VERSION 5.7 ;
BUSBITCHARS "[]" ;
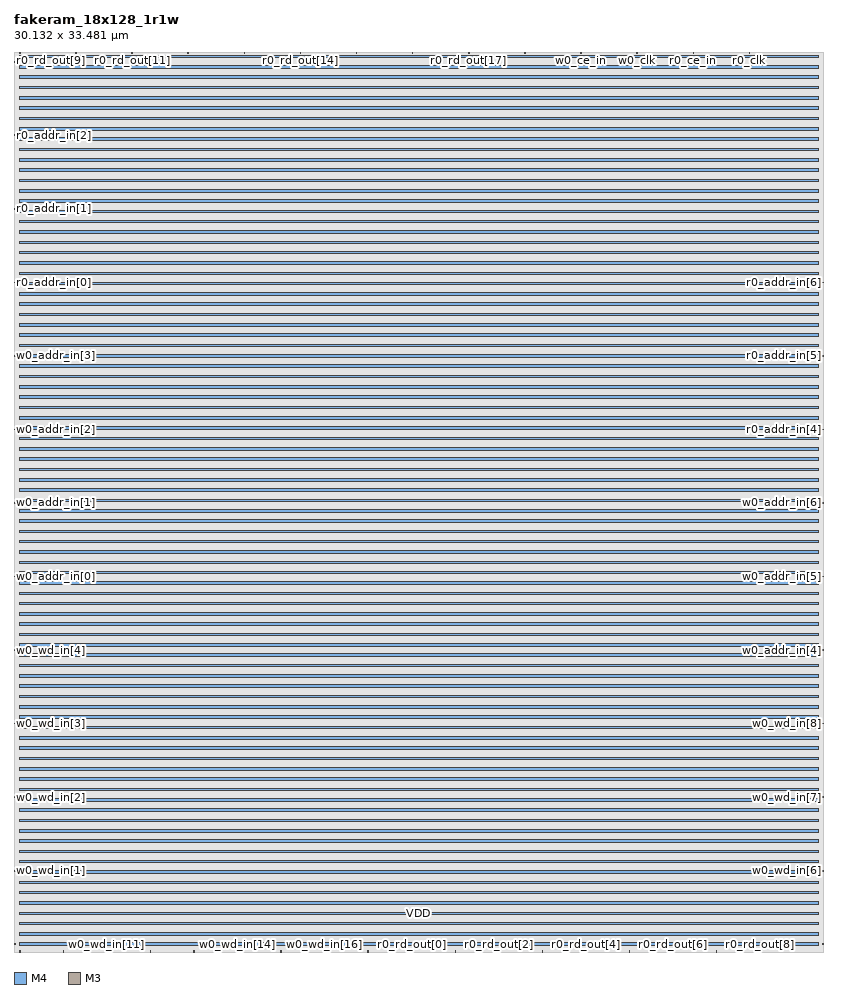
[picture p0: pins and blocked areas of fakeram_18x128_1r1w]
MACRO fakeram_18x128_1r1w
  FOREIGN fakeram_18x128_1r1w 0 0 ;
  SYMMETRY X Y R90 ;
  SIZE 30.132 BY 33.481 ;
  CLASS BLOCK ;
  PIN w0_wd_in[0]
    DIRECTION INPUT ;
    USE SIGNAL ;
    SHAPE ABUTMENT ;
    PORT
      LAYER M4 ;
      RECT 0.000 0.276 0.072 0.300 ;
    END
  END w0_wd_in[0]
  PIN w0_wd_in[1]
    DIRECTION INPUT ;
    USE SIGNAL ;
    SHAPE ABUTMENT ;
    PORT
      LAYER M4 ;
      RECT 0.000 3.012 0.072 3.036 ;
    END
  END w0_wd_in[1]
  PIN w0_wd_in[2]
    DIRECTION INPUT ;
    USE SIGNAL ;
    SHAPE ABUTMENT ;
    PORT
      LAYER M4 ;
      RECT 0.000 5.748 0.072 5.772 ;
    END
  END w0_wd_in[2]
  PIN w0_wd_in[3]
    DIRECTION INPUT ;
    USE SIGNAL ;
    SHAPE ABUTMENT ;
    PORT
      LAYER M4 ;
      RECT 0.000 8.484 0.072 8.508 ;
    END
  END w0_wd_in[3]
  PIN w0_wd_in[4]
    DIRECTION INPUT ;
    USE SIGNAL ;
    SHAPE ABUTMENT ;
    PORT
      LAYER M4 ;
      RECT 0.000 11.220 0.072 11.244 ;
    END
  END w0_wd_in[4]
  PIN w0_wd_in[5]
    DIRECTION INPUT ;
    USE SIGNAL ;
    SHAPE ABUTMENT ;
    PORT
      LAYER M4 ;
      RECT 30.060 0.276 30.132 0.300 ;
    END
  END w0_wd_in[5]
  PIN w0_wd_in[6]
    DIRECTION INPUT ;
    USE SIGNAL ;
    SHAPE ABUTMENT ;
    PORT
      LAYER M4 ;
      RECT 30.060 3.012 30.132 3.036 ;
    END
  END w0_wd_in[6]
  PIN w0_wd_in[7]
    DIRECTION INPUT ;
    USE SIGNAL ;
    SHAPE ABUTMENT ;
    PORT
      LAYER M4 ;
      RECT 30.060 5.748 30.132 5.772 ;
    END
  END w0_wd_in[7]
  PIN w0_wd_in[8]
    DIRECTION INPUT ;
    USE SIGNAL ;
    SHAPE ABUTMENT ;
    PORT
      LAYER M4 ;
      RECT 30.060 8.484 30.132 8.508 ;
    END
  END w0_wd_in[8]
  PIN w0_wd_in[9]
    DIRECTION INPUT ;
    USE SIGNAL ;
    SHAPE ABUTMENT ;
    PORT
      LAYER M3 ;
      RECT 0.207 0.000 0.225 0.054 ;
    END
  END w0_wd_in[9]
  PIN w0_wd_in[10]
    DIRECTION INPUT ;
    USE SIGNAL ;
    SHAPE ABUTMENT ;
    PORT
      LAYER M3 ;
      RECT 1.827 0.000 1.845 0.054 ;
    END
  END w0_wd_in[10]
  PIN w0_wd_in[11]
    DIRECTION INPUT ;
    USE SIGNAL ;
    SHAPE ABUTMENT ;
    PORT
      LAYER M3 ;
      RECT 3.447 0.000 3.465 0.054 ;
    END
  END w0_wd_in[11]
  PIN w0_wd_in[12]
    DIRECTION INPUT ;
    USE SIGNAL ;
    SHAPE ABUTMENT ;
    PORT
      LAYER M3 ;
      RECT 5.067 0.000 5.085 0.054 ;
    END
  END w0_wd_in[12]
  PIN w0_wd_in[13]
    DIRECTION INPUT ;
    USE SIGNAL ;
    SHAPE ABUTMENT ;
    PORT
      LAYER M3 ;
      RECT 6.687 0.000 6.705 0.054 ;
    END
  END w0_wd_in[13]
  PIN w0_wd_in[14]
    DIRECTION INPUT ;
    USE SIGNAL ;
    SHAPE ABUTMENT ;
    PORT
      LAYER M3 ;
      RECT 8.307 0.000 8.325 0.054 ;
    END
  END w0_wd_in[14]
  PIN w0_wd_in[15]
    DIRECTION INPUT ;
    USE SIGNAL ;
    SHAPE ABUTMENT ;
    PORT
      LAYER M3 ;
      RECT 9.927 0.000 9.945 0.054 ;
    END
  END w0_wd_in[15]
  PIN w0_wd_in[16]
    DIRECTION INPUT ;
    USE SIGNAL ;
    SHAPE ABUTMENT ;
    PORT
      LAYER M3 ;
      RECT 11.547 0.000 11.565 0.054 ;
    END
  END w0_wd_in[16]
  PIN w0_wd_in[17]
    DIRECTION INPUT ;
    USE SIGNAL ;
    SHAPE ABUTMENT ;
    PORT
      LAYER M3 ;
      RECT 13.167 0.000 13.185 0.054 ;
    END
  END w0_wd_in[17]
  PIN r0_rd_out[0]
    DIRECTION OUTPUT ;
    USE SIGNAL ;
    SHAPE ABUTMENT ;
    PORT
      LAYER M3 ;
      RECT 14.787 0.000 14.805 0.054 ;
    END
  END r0_rd_out[0]
  PIN r0_rd_out[1]
    DIRECTION OUTPUT ;
    USE SIGNAL ;
    SHAPE ABUTMENT ;
    PORT
      LAYER M3 ;
      RECT 16.407 0.000 16.425 0.054 ;
    END
  END r0_rd_out[1]
  PIN r0_rd_out[2]
    DIRECTION OUTPUT ;
    USE SIGNAL ;
    SHAPE ABUTMENT ;
    PORT
      LAYER M3 ;
      RECT 18.027 0.000 18.045 0.054 ;
    END
  END r0_rd_out[2]
  PIN r0_rd_out[3]
    DIRECTION OUTPUT ;
    USE SIGNAL ;
    SHAPE ABUTMENT ;
    PORT
      LAYER M3 ;
      RECT 19.647 0.000 19.665 0.054 ;
    END
  END r0_rd_out[3]
  PIN r0_rd_out[4]
    DIRECTION OUTPUT ;
    USE SIGNAL ;
    SHAPE ABUTMENT ;
    PORT
      LAYER M3 ;
      RECT 21.267 0.000 21.285 0.054 ;
    END
  END r0_rd_out[4]
  PIN r0_rd_out[5]
    DIRECTION OUTPUT ;
    USE SIGNAL ;
    SHAPE ABUTMENT ;
    PORT
      LAYER M3 ;
      RECT 22.887 0.000 22.905 0.054 ;
    END
  END r0_rd_out[5]
  PIN r0_rd_out[6]
    DIRECTION OUTPUT ;
    USE SIGNAL ;
    SHAPE ABUTMENT ;
    PORT
      LAYER M3 ;
      RECT 24.507 0.000 24.525 0.054 ;
    END
  END r0_rd_out[6]
  PIN r0_rd_out[7]
    DIRECTION OUTPUT ;
    USE SIGNAL ;
    SHAPE ABUTMENT ;
    PORT
      LAYER M3 ;
      RECT 26.127 0.000 26.145 0.054 ;
    END
  END r0_rd_out[7]
  PIN r0_rd_out[8]
    DIRECTION OUTPUT ;
    USE SIGNAL ;
    SHAPE ABUTMENT ;
    PORT
      LAYER M3 ;
      RECT 27.747 0.000 27.765 0.054 ;
    END
  END r0_rd_out[8]
  PIN r0_rd_out[9]
    DIRECTION OUTPUT ;
    USE SIGNAL ;
    SHAPE ABUTMENT ;
    PORT
      LAYER M3 ;
      RECT 0.207 33.427 0.225 33.481 ;
    END
  END r0_rd_out[9]
  PIN r0_rd_out[10]
    DIRECTION OUTPUT ;
    USE SIGNAL ;
    SHAPE ABUTMENT ;
    PORT
      LAYER M3 ;
      RECT 2.295 33.427 2.313 33.481 ;
    END
  END r0_rd_out[10]
  PIN r0_rd_out[11]
    DIRECTION OUTPUT ;
    USE SIGNAL ;
    SHAPE ABUTMENT ;
    PORT
      LAYER M3 ;
      RECT 4.383 33.427 4.401 33.481 ;
    END
  END r0_rd_out[11]
  PIN r0_rd_out[12]
    DIRECTION OUTPUT ;
    USE SIGNAL ;
    SHAPE ABUTMENT ;
    PORT
      LAYER M3 ;
      RECT 6.471 33.427 6.489 33.481 ;
    END
  END r0_rd_out[12]
  PIN r0_rd_out[13]
    DIRECTION OUTPUT ;
    USE SIGNAL ;
    SHAPE ABUTMENT ;
    PORT
      LAYER M3 ;
      RECT 8.559 33.427 8.577 33.481 ;
    END
  END r0_rd_out[13]
  PIN r0_rd_out[14]
    DIRECTION OUTPUT ;
    USE SIGNAL ;
    SHAPE ABUTMENT ;
    PORT
      LAYER M3 ;
      RECT 10.647 33.427 10.665 33.481 ;
    END
  END r0_rd_out[14]
  PIN r0_rd_out[15]
    DIRECTION OUTPUT ;
    USE SIGNAL ;
    SHAPE ABUTMENT ;
    PORT
      LAYER M3 ;
      RECT 12.735 33.427 12.753 33.481 ;
    END
  END r0_rd_out[15]
  PIN r0_rd_out[16]
    DIRECTION OUTPUT ;
    USE SIGNAL ;
    SHAPE ABUTMENT ;
    PORT
      LAYER M3 ;
      RECT 14.823 33.427 14.841 33.481 ;
    END
  END r0_rd_out[16]
  PIN r0_rd_out[17]
    DIRECTION OUTPUT ;
    USE SIGNAL ;
    SHAPE ABUTMENT ;
    PORT
      LAYER M3 ;
      RECT 16.911 33.427 16.929 33.481 ;
    END
  END r0_rd_out[17]
  PIN w0_addr_in[0]
    DIRECTION INPUT ;
    USE SIGNAL ;
    SHAPE ABUTMENT ;
    PORT
      LAYER M4 ;
      RECT 0.000 13.956 0.072 13.980 ;
    END
  END w0_addr_in[0]
  PIN w0_addr_in[1]
    DIRECTION INPUT ;
    USE SIGNAL ;
    SHAPE ABUTMENT ;
    PORT
      LAYER M4 ;
      RECT 0.000 16.692 0.072 16.716 ;
    END
  END w0_addr_in[1]
  PIN w0_addr_in[2]
    DIRECTION INPUT ;
    USE SIGNAL ;
    SHAPE ABUTMENT ;
    PORT
      LAYER M4 ;
      RECT 0.000 19.428 0.072 19.452 ;
    END
  END w0_addr_in[2]
  PIN w0_addr_in[3]
    DIRECTION INPUT ;
    USE SIGNAL ;
    SHAPE ABUTMENT ;
    PORT
      LAYER M4 ;
      RECT 0.000 22.164 0.072 22.188 ;
    END
  END w0_addr_in[3]
  PIN w0_addr_in[4]
    DIRECTION INPUT ;
    USE SIGNAL ;
    SHAPE ABUTMENT ;
    PORT
      LAYER M4 ;
      RECT 30.060 11.220 30.132 11.244 ;
    END
  END w0_addr_in[4]
  PIN w0_addr_in[5]
    DIRECTION INPUT ;
    USE SIGNAL ;
    SHAPE ABUTMENT ;
    PORT
      LAYER M4 ;
      RECT 30.060 13.956 30.132 13.980 ;
    END
  END w0_addr_in[5]
  PIN w0_addr_in[6]
    DIRECTION INPUT ;
    USE SIGNAL ;
    SHAPE ABUTMENT ;
    PORT
      LAYER M4 ;
      RECT 30.060 16.692 30.132 16.716 ;
    END
  END w0_addr_in[6]
  PIN r0_addr_in[0]
    DIRECTION INPUT ;
    USE SIGNAL ;
    SHAPE ABUTMENT ;
    PORT
      LAYER M4 ;
      RECT 0.000 24.900 0.072 24.924 ;
    END
  END r0_addr_in[0]
  PIN r0_addr_in[1]
    DIRECTION INPUT ;
    USE SIGNAL ;
    SHAPE ABUTMENT ;
    PORT
      LAYER M4 ;
      RECT 0.000 27.636 0.072 27.660 ;
    END
  END r0_addr_in[1]
  PIN r0_addr_in[2]
    DIRECTION INPUT ;
    USE SIGNAL ;
    SHAPE ABUTMENT ;
    PORT
      LAYER M4 ;
      RECT 0.000 30.372 0.072 30.396 ;
    END
  END r0_addr_in[2]
  PIN r0_addr_in[3]
    DIRECTION INPUT ;
    USE SIGNAL ;
    SHAPE ABUTMENT ;
    PORT
      LAYER M4 ;
      RECT 0.000 33.108 0.072 33.132 ;
    END
  END r0_addr_in[3]
  PIN r0_addr_in[4]
    DIRECTION INPUT ;
    USE SIGNAL ;
    SHAPE ABUTMENT ;
    PORT
      LAYER M4 ;
      RECT 30.060 19.428 30.132 19.452 ;
    END
  END r0_addr_in[4]
  PIN r0_addr_in[5]
    DIRECTION INPUT ;
    USE SIGNAL ;
    SHAPE ABUTMENT ;
    PORT
      LAYER M4 ;
      RECT 30.060 22.164 30.132 22.188 ;
    END
  END r0_addr_in[5]
  PIN r0_addr_in[6]
    DIRECTION INPUT ;
    USE SIGNAL ;
    SHAPE ABUTMENT ;
    PORT
      LAYER M4 ;
      RECT 30.060 24.900 30.132 24.924 ;
    END
  END r0_addr_in[6]
  PIN w0_we_in
    DIRECTION INPUT ;
    USE SIGNAL ;
    SHAPE ABUTMENT ;
    PORT
      LAYER M3 ;
      RECT 18.999 33.427 19.017 33.481 ;
    END
  END w0_we_in
  PIN w0_ce_in
    DIRECTION INPUT ;
    USE SIGNAL ;
    SHAPE ABUTMENT ;
    PORT
      LAYER M3 ;
      RECT 21.087 33.427 21.105 33.481 ;
    END
  END w0_ce_in
  PIN w0_clk
    DIRECTION INPUT ;
    USE SIGNAL ;
    SHAPE ABUTMENT ;
    PORT
      LAYER M3 ;
      RECT 23.175 33.427 23.193 33.481 ;
    END
  END w0_clk
  PIN r0_ce_in
    DIRECTION INPUT ;
    USE SIGNAL ;
    SHAPE ABUTMENT ;
    PORT
      LAYER M3 ;
      RECT 25.263 33.427 25.281 33.481 ;
    END
  END r0_ce_in
  PIN r0_clk
    DIRECTION INPUT ;
    USE SIGNAL ;
    SHAPE ABUTMENT ;
    PORT
      LAYER M3 ;
      RECT 27.351 33.427 27.369 33.481 ;
    END
  END r0_clk
  PIN VSS
    DIRECTION INOUT ;
    USE GROUND ;
    PORT
      LAYER M4 ;
      RECT 0.216 0.240 29.916 0.336 ;
      RECT 0.216 1.008 29.916 1.104 ;
      RECT 0.216 1.776 29.916 1.872 ;
      RECT 0.216 2.544 29.916 2.640 ;
      RECT 0.216 3.312 29.916 3.408 ;
      RECT 0.216 4.080 29.916 4.176 ;
      RECT 0.216 4.848 29.916 4.944 ;
      RECT 0.216 5.616 29.916 5.712 ;
      RECT 0.216 6.384 29.916 6.480 ;
      RECT 0.216 7.152 29.916 7.248 ;
      RECT 0.216 7.920 29.916 8.016 ;
      RECT 0.216 8.688 29.916 8.784 ;
      RECT 0.216 9.456 29.916 9.552 ;
      RECT 0.216 10.224 29.916 10.320 ;
      RECT 0.216 10.992 29.916 11.088 ;
      RECT 0.216 11.760 29.916 11.856 ;
      RECT 0.216 12.528 29.916 12.624 ;
      RECT 0.216 13.296 29.916 13.392 ;
      RECT 0.216 14.064 29.916 14.160 ;
      RECT 0.216 14.832 29.916 14.928 ;
      RECT 0.216 15.600 29.916 15.696 ;
      RECT 0.216 16.368 29.916 16.464 ;
      RECT 0.216 17.136 29.916 17.232 ;
      RECT 0.216 17.904 29.916 18.000 ;
      RECT 0.216 18.672 29.916 18.768 ;
      RECT 0.216 19.440 29.916 19.536 ;
      RECT 0.216 20.208 29.916 20.304 ;
      RECT 0.216 20.976 29.916 21.072 ;
      RECT 0.216 21.744 29.916 21.840 ;
      RECT 0.216 22.512 29.916 22.608 ;
      RECT 0.216 23.280 29.916 23.376 ;
      RECT 0.216 24.048 29.916 24.144 ;
      RECT 0.216 24.816 29.916 24.912 ;
      RECT 0.216 25.584 29.916 25.680 ;
      RECT 0.216 26.352 29.916 26.448 ;
      RECT 0.216 27.120 29.916 27.216 ;
      RECT 0.216 27.888 29.916 27.984 ;
      RECT 0.216 28.656 29.916 28.752 ;
      RECT 0.216 29.424 29.916 29.520 ;
      RECT 0.216 30.192 29.916 30.288 ;
      RECT 0.216 30.960 29.916 31.056 ;
      RECT 0.216 31.728 29.916 31.824 ;
      RECT 0.216 32.496 29.916 32.592 ;
      RECT 0.216 33.264 29.916 33.360 ;
    END
  END VSS
  PIN VDD
    DIRECTION INOUT ;
    USE POWER ;
    PORT
      LAYER M4 ;
      RECT 0.216 0.624 29.916 0.720 ;
      RECT 0.216 1.392 29.916 1.488 ;
      RECT 0.216 2.160 29.916 2.256 ;
      RECT 0.216 2.928 29.916 3.024 ;
      RECT 0.216 3.696 29.916 3.792 ;
      RECT 0.216 4.464 29.916 4.560 ;
      RECT 0.216 5.232 29.916 5.328 ;
      RECT 0.216 6.000 29.916 6.096 ;
      RECT 0.216 6.768 29.916 6.864 ;
      RECT 0.216 7.536 29.916 7.632 ;
      RECT 0.216 8.304 29.916 8.400 ;
      RECT 0.216 9.072 29.916 9.168 ;
      RECT 0.216 9.840 29.916 9.936 ;
      RECT 0.216 10.608 29.916 10.704 ;
      RECT 0.216 11.376 29.916 11.472 ;
      RECT 0.216 12.144 29.916 12.240 ;
      RECT 0.216 12.912 29.916 13.008 ;
      RECT 0.216 13.680 29.916 13.776 ;
      RECT 0.216 14.448 29.916 14.544 ;
      RECT 0.216 15.216 29.916 15.312 ;
      RECT 0.216 15.984 29.916 16.080 ;
      RECT 0.216 16.752 29.916 16.848 ;
      RECT 0.216 17.520 29.916 17.616 ;
      RECT 0.216 18.288 29.916 18.384 ;
      RECT 0.216 19.056 29.916 19.152 ;
      RECT 0.216 19.824 29.916 19.920 ;
      RECT 0.216 20.592 29.916 20.688 ;
      RECT 0.216 21.360 29.916 21.456 ;
      RECT 0.216 22.128 29.916 22.224 ;
      RECT 0.216 22.896 29.916 22.992 ;
      RECT 0.216 23.664 29.916 23.760 ;
      RECT 0.216 24.432 29.916 24.528 ;
      RECT 0.216 25.200 29.916 25.296 ;
      RECT 0.216 25.968 29.916 26.064 ;
      RECT 0.216 26.736 29.916 26.832 ;
      RECT 0.216 27.504 29.916 27.600 ;
      RECT 0.216 28.272 29.916 28.368 ;
      RECT 0.216 29.040 29.916 29.136 ;
      RECT 0.216 29.808 29.916 29.904 ;
      RECT 0.216 30.576 29.916 30.672 ;
      RECT 0.216 31.344 29.916 31.440 ;
      RECT 0.216 32.112 29.916 32.208 ;
      RECT 0.216 32.880 29.916 32.976 ;
    END
  END VDD
  OBS
    LAYER M1 ;
    RECT 0 0 30.132 33.481 ;
    LAYER M2 ;
    RECT 0 0 30.132 33.481 ;
    LAYER M3 ;
    RECT 0 0 30.132 33.481 ;
    LAYER M4 ;
    RECT 0 0 30.132 33.481 ;
  END
END fakeram_18x128_1r1w

END LIBRARY
